# Generated by FakeRAM 2.0
VERSION 5.7 ;
BUSBITCHARS "[]" ;
PROPERTYDEFINITIONS
  MACRO width INTEGER ;
  MACRO depth INTEGER ;
  MACRO banks INTEGER ;
END PROPERTYDEFINITIONS
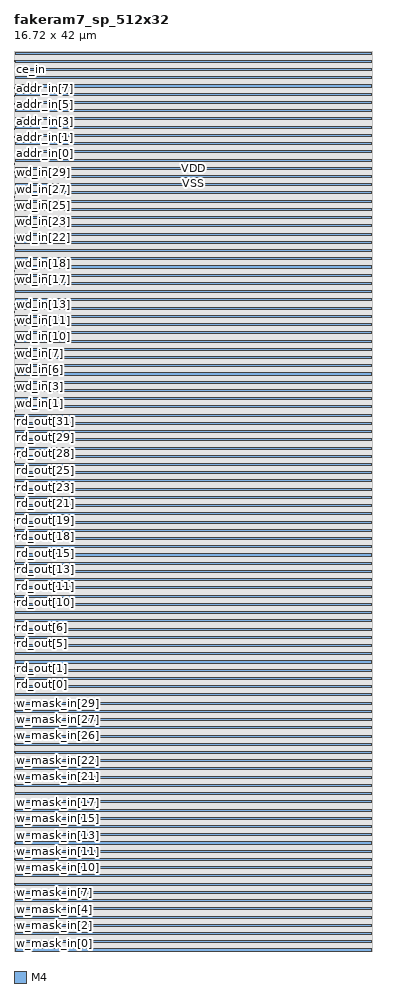
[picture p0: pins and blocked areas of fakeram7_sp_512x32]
MACRO fakeram7_sp_512x32
  PROPERTY width 32 ;
  PROPERTY depth 512 ;
  PROPERTY banks 4 ;
  FOREIGN fakeram7_sp_512x32 0 0 ;
  SYMMETRY X Y ;
  SIZE 16.720 BY 42.000 ;
  CLASS BLOCK ;
  PIN w_mask_in[0]
    DIRECTION INPUT ;
    USE SIGNAL ;
    SHAPE ABUTMENT ;
    PORT
      LAYER M4 ;
      RECT 0.000 0.048 0.024 0.072 ;
    END
  END w_mask_in[0]
  PIN w_mask_in[1]
    DIRECTION INPUT ;
    USE SIGNAL ;
    SHAPE ABUTMENT ;
    PORT
      LAYER M4 ;
      RECT 0.000 0.432 0.024 0.456 ;
    END
  END w_mask_in[1]
  PIN w_mask_in[2]
    DIRECTION INPUT ;
    USE SIGNAL ;
    SHAPE ABUTMENT ;
    PORT
      LAYER M4 ;
      RECT 0.000 0.816 0.024 0.840 ;
    END
  END w_mask_in[2]
  PIN w_mask_in[3]
    DIRECTION INPUT ;
    USE SIGNAL ;
    SHAPE ABUTMENT ;
    PORT
      LAYER M4 ;
      RECT 0.000 1.200 0.024 1.224 ;
    END
  END w_mask_in[3]
  PIN w_mask_in[4]
    DIRECTION INPUT ;
    USE SIGNAL ;
    SHAPE ABUTMENT ;
    PORT
      LAYER M4 ;
      RECT 0.000 1.584 0.024 1.608 ;
    END
  END w_mask_in[4]
  PIN w_mask_in[5]
    DIRECTION INPUT ;
    USE SIGNAL ;
    SHAPE ABUTMENT ;
    PORT
      LAYER M4 ;
      RECT 0.000 1.968 0.024 1.992 ;
    END
  END w_mask_in[5]
  PIN w_mask_in[6]
    DIRECTION INPUT ;
    USE SIGNAL ;
    SHAPE ABUTMENT ;
    PORT
      LAYER M4 ;
      RECT 0.000 2.352 0.024 2.376 ;
    END
  END w_mask_in[6]
  PIN w_mask_in[7]
    DIRECTION INPUT ;
    USE SIGNAL ;
    SHAPE ABUTMENT ;
    PORT
      LAYER M4 ;
      RECT 0.000 2.736 0.024 2.760 ;
    END
  END w_mask_in[7]
  PIN w_mask_in[8]
    DIRECTION INPUT ;
    USE SIGNAL ;
    SHAPE ABUTMENT ;
    PORT
      LAYER M4 ;
      RECT 0.000 3.120 0.024 3.144 ;
    END
  END w_mask_in[8]
  PIN w_mask_in[9]
    DIRECTION INPUT ;
    USE SIGNAL ;
    SHAPE ABUTMENT ;
    PORT
      LAYER M4 ;
      RECT 0.000 3.504 0.024 3.528 ;
    END
  END w_mask_in[9]
  PIN w_mask_in[10]
    DIRECTION INPUT ;
    USE SIGNAL ;
    SHAPE ABUTMENT ;
    PORT
      LAYER M4 ;
      RECT 0.000 3.888 0.024 3.912 ;
    END
  END w_mask_in[10]
  PIN w_mask_in[11]
    DIRECTION INPUT ;
    USE SIGNAL ;
    SHAPE ABUTMENT ;
    PORT
      LAYER M4 ;
      RECT 0.000 4.272 0.024 4.296 ;
    END
  END w_mask_in[11]
  PIN w_mask_in[12]
    DIRECTION INPUT ;
    USE SIGNAL ;
    SHAPE ABUTMENT ;
    PORT
      LAYER M4 ;
      RECT 0.000 4.656 0.024 4.680 ;
    END
  END w_mask_in[12]
  PIN w_mask_in[13]
    DIRECTION INPUT ;
    USE SIGNAL ;
    SHAPE ABUTMENT ;
    PORT
      LAYER M4 ;
      RECT 0.000 5.040 0.024 5.064 ;
    END
  END w_mask_in[13]
  PIN w_mask_in[14]
    DIRECTION INPUT ;
    USE SIGNAL ;
    SHAPE ABUTMENT ;
    PORT
      LAYER M4 ;
      RECT 0.000 5.424 0.024 5.448 ;
    END
  END w_mask_in[14]
  PIN w_mask_in[15]
    DIRECTION INPUT ;
    USE SIGNAL ;
    SHAPE ABUTMENT ;
    PORT
      LAYER M4 ;
      RECT 0.000 5.808 0.024 5.832 ;
    END
  END w_mask_in[15]
  PIN w_mask_in[16]
    DIRECTION INPUT ;
    USE SIGNAL ;
    SHAPE ABUTMENT ;
    PORT
      LAYER M4 ;
      RECT 0.000 6.192 0.024 6.216 ;
    END
  END w_mask_in[16]
  PIN w_mask_in[17]
    DIRECTION INPUT ;
    USE SIGNAL ;
    SHAPE ABUTMENT ;
    PORT
      LAYER M4 ;
      RECT 0.000 6.576 0.024 6.600 ;
    END
  END w_mask_in[17]
  PIN w_mask_in[18]
    DIRECTION INPUT ;
    USE SIGNAL ;
    SHAPE ABUTMENT ;
    PORT
      LAYER M4 ;
      RECT 0.000 6.960 0.024 6.984 ;
    END
  END w_mask_in[18]
  PIN w_mask_in[19]
    DIRECTION INPUT ;
    USE SIGNAL ;
    SHAPE ABUTMENT ;
    PORT
      LAYER M4 ;
      RECT 0.000 7.344 0.024 7.368 ;
    END
  END w_mask_in[19]
  PIN w_mask_in[20]
    DIRECTION INPUT ;
    USE SIGNAL ;
    SHAPE ABUTMENT ;
    PORT
      LAYER M4 ;
      RECT 0.000 7.728 0.024 7.752 ;
    END
  END w_mask_in[20]
  PIN w_mask_in[21]
    DIRECTION INPUT ;
    USE SIGNAL ;
    SHAPE ABUTMENT ;
    PORT
      LAYER M4 ;
      RECT 0.000 8.112 0.024 8.136 ;
    END
  END w_mask_in[21]
  PIN w_mask_in[22]
    DIRECTION INPUT ;
    USE SIGNAL ;
    SHAPE ABUTMENT ;
    PORT
      LAYER M4 ;
      RECT 0.000 8.496 0.024 8.520 ;
    END
  END w_mask_in[22]
  PIN w_mask_in[23]
    DIRECTION INPUT ;
    USE SIGNAL ;
    SHAPE ABUTMENT ;
    PORT
      LAYER M4 ;
      RECT 0.000 8.880 0.024 8.904 ;
    END
  END w_mask_in[23]
  PIN w_mask_in[24]
    DIRECTION INPUT ;
    USE SIGNAL ;
    SHAPE ABUTMENT ;
    PORT
      LAYER M4 ;
      RECT 0.000 9.264 0.024 9.288 ;
    END
  END w_mask_in[24]
  PIN w_mask_in[25]
    DIRECTION INPUT ;
    USE SIGNAL ;
    SHAPE ABUTMENT ;
    PORT
      LAYER M4 ;
      RECT 0.000 9.648 0.024 9.672 ;
    END
  END w_mask_in[25]
  PIN w_mask_in[26]
    DIRECTION INPUT ;
    USE SIGNAL ;
    SHAPE ABUTMENT ;
    PORT
      LAYER M4 ;
      RECT 0.000 10.032 0.024 10.056 ;
    END
  END w_mask_in[26]
  PIN w_mask_in[27]
    DIRECTION INPUT ;
    USE SIGNAL ;
    SHAPE ABUTMENT ;
    PORT
      LAYER M4 ;
      RECT 0.000 10.416 0.024 10.440 ;
    END
  END w_mask_in[27]
  PIN w_mask_in[28]
    DIRECTION INPUT ;
    USE SIGNAL ;
    SHAPE ABUTMENT ;
    PORT
      LAYER M4 ;
      RECT 0.000 10.800 0.024 10.824 ;
    END
  END w_mask_in[28]
  PIN w_mask_in[29]
    DIRECTION INPUT ;
    USE SIGNAL ;
    SHAPE ABUTMENT ;
    PORT
      LAYER M4 ;
      RECT 0.000 11.184 0.024 11.208 ;
    END
  END w_mask_in[29]
  PIN w_mask_in[30]
    DIRECTION INPUT ;
    USE SIGNAL ;
    SHAPE ABUTMENT ;
    PORT
      LAYER M4 ;
      RECT 0.000 11.568 0.024 11.592 ;
    END
  END w_mask_in[30]
  PIN w_mask_in[31]
    DIRECTION INPUT ;
    USE SIGNAL ;
    SHAPE ABUTMENT ;
    PORT
      LAYER M4 ;
      RECT 0.000 11.952 0.024 11.976 ;
    END
  END w_mask_in[31]
  PIN rd_out[0]
    DIRECTION OUTPUT ;
    USE SIGNAL ;
    SHAPE ABUTMENT ;
    PORT
      LAYER M4 ;
      RECT 0.000 12.432 0.024 12.456 ;
    END
  END rd_out[0]
  PIN rd_out[1]
    DIRECTION OUTPUT ;
    USE SIGNAL ;
    SHAPE ABUTMENT ;
    PORT
      LAYER M4 ;
      RECT 0.000 12.816 0.024 12.840 ;
    END
  END rd_out[1]
  PIN rd_out[2]
    DIRECTION OUTPUT ;
    USE SIGNAL ;
    SHAPE ABUTMENT ;
    PORT
      LAYER M4 ;
      RECT 0.000 13.200 0.024 13.224 ;
    END
  END rd_out[2]
  PIN rd_out[3]
    DIRECTION OUTPUT ;
    USE SIGNAL ;
    SHAPE ABUTMENT ;
    PORT
      LAYER M4 ;
      RECT 0.000 13.584 0.024 13.608 ;
    END
  END rd_out[3]
  PIN rd_out[4]
    DIRECTION OUTPUT ;
    USE SIGNAL ;
    SHAPE ABUTMENT ;
    PORT
      LAYER M4 ;
      RECT 0.000 13.968 0.024 13.992 ;
    END
  END rd_out[4]
  PIN rd_out[5]
    DIRECTION OUTPUT ;
    USE SIGNAL ;
    SHAPE ABUTMENT ;
    PORT
      LAYER M4 ;
      RECT 0.000 14.352 0.024 14.376 ;
    END
  END rd_out[5]
  PIN rd_out[6]
    DIRECTION OUTPUT ;
    USE SIGNAL ;
    SHAPE ABUTMENT ;
    PORT
      LAYER M4 ;
      RECT 0.000 14.736 0.024 14.760 ;
    END
  END rd_out[6]
  PIN rd_out[7]
    DIRECTION OUTPUT ;
    USE SIGNAL ;
    SHAPE ABUTMENT ;
    PORT
      LAYER M4 ;
      RECT 0.000 15.120 0.024 15.144 ;
    END
  END rd_out[7]
  PIN rd_out[8]
    DIRECTION OUTPUT ;
    USE SIGNAL ;
    SHAPE ABUTMENT ;
    PORT
      LAYER M4 ;
      RECT 0.000 15.504 0.024 15.528 ;
    END
  END rd_out[8]
  PIN rd_out[9]
    DIRECTION OUTPUT ;
    USE SIGNAL ;
    SHAPE ABUTMENT ;
    PORT
      LAYER M4 ;
      RECT 0.000 15.888 0.024 15.912 ;
    END
  END rd_out[9]
  PIN rd_out[10]
    DIRECTION OUTPUT ;
    USE SIGNAL ;
    SHAPE ABUTMENT ;
    PORT
      LAYER M4 ;
      RECT 0.000 16.272 0.024 16.296 ;
    END
  END rd_out[10]
  PIN rd_out[11]
    DIRECTION OUTPUT ;
    USE SIGNAL ;
    SHAPE ABUTMENT ;
    PORT
      LAYER M4 ;
      RECT 0.000 16.656 0.024 16.680 ;
    END
  END rd_out[11]
  PIN rd_out[12]
    DIRECTION OUTPUT ;
    USE SIGNAL ;
    SHAPE ABUTMENT ;
    PORT
      LAYER M4 ;
      RECT 0.000 17.040 0.024 17.064 ;
    END
  END rd_out[12]
  PIN rd_out[13]
    DIRECTION OUTPUT ;
    USE SIGNAL ;
    SHAPE ABUTMENT ;
    PORT
      LAYER M4 ;
      RECT 0.000 17.424 0.024 17.448 ;
    END
  END rd_out[13]
  PIN rd_out[14]
    DIRECTION OUTPUT ;
    USE SIGNAL ;
    SHAPE ABUTMENT ;
    PORT
      LAYER M4 ;
      RECT 0.000 17.808 0.024 17.832 ;
    END
  END rd_out[14]
  PIN rd_out[15]
    DIRECTION OUTPUT ;
    USE SIGNAL ;
    SHAPE ABUTMENT ;
    PORT
      LAYER M4 ;
      RECT 0.000 18.192 0.024 18.216 ;
    END
  END rd_out[15]
  PIN rd_out[16]
    DIRECTION OUTPUT ;
    USE SIGNAL ;
    SHAPE ABUTMENT ;
    PORT
      LAYER M4 ;
      RECT 0.000 18.576 0.024 18.600 ;
    END
  END rd_out[16]
  PIN rd_out[17]
    DIRECTION OUTPUT ;
    USE SIGNAL ;
    SHAPE ABUTMENT ;
    PORT
      LAYER M4 ;
      RECT 0.000 18.960 0.024 18.984 ;
    END
  END rd_out[17]
  PIN rd_out[18]
    DIRECTION OUTPUT ;
    USE SIGNAL ;
    SHAPE ABUTMENT ;
    PORT
      LAYER M4 ;
      RECT 0.000 19.344 0.024 19.368 ;
    END
  END rd_out[18]
  PIN rd_out[19]
    DIRECTION OUTPUT ;
    USE SIGNAL ;
    SHAPE ABUTMENT ;
    PORT
      LAYER M4 ;
      RECT 0.000 19.728 0.024 19.752 ;
    END
  END rd_out[19]
  PIN rd_out[20]
    DIRECTION OUTPUT ;
    USE SIGNAL ;
    SHAPE ABUTMENT ;
    PORT
      LAYER M4 ;
      RECT 0.000 20.112 0.024 20.136 ;
    END
  END rd_out[20]
  PIN rd_out[21]
    DIRECTION OUTPUT ;
    USE SIGNAL ;
    SHAPE ABUTMENT ;
    PORT
      LAYER M4 ;
      RECT 0.000 20.496 0.024 20.520 ;
    END
  END rd_out[21]
  PIN rd_out[22]
    DIRECTION OUTPUT ;
    USE SIGNAL ;
    SHAPE ABUTMENT ;
    PORT
      LAYER M4 ;
      RECT 0.000 20.880 0.024 20.904 ;
    END
  END rd_out[22]
  PIN rd_out[23]
    DIRECTION OUTPUT ;
    USE SIGNAL ;
    SHAPE ABUTMENT ;
    PORT
      LAYER M4 ;
      RECT 0.000 21.264 0.024 21.288 ;
    END
  END rd_out[23]
  PIN rd_out[24]
    DIRECTION OUTPUT ;
    USE SIGNAL ;
    SHAPE ABUTMENT ;
    PORT
      LAYER M4 ;
      RECT 0.000 21.648 0.024 21.672 ;
    END
  END rd_out[24]
  PIN rd_out[25]
    DIRECTION OUTPUT ;
    USE SIGNAL ;
    SHAPE ABUTMENT ;
    PORT
      LAYER M4 ;
      RECT 0.000 22.032 0.024 22.056 ;
    END
  END rd_out[25]
  PIN rd_out[26]
    DIRECTION OUTPUT ;
    USE SIGNAL ;
    SHAPE ABUTMENT ;
    PORT
      LAYER M4 ;
      RECT 0.000 22.416 0.024 22.440 ;
    END
  END rd_out[26]
  PIN rd_out[27]
    DIRECTION OUTPUT ;
    USE SIGNAL ;
    SHAPE ABUTMENT ;
    PORT
      LAYER M4 ;
      RECT 0.000 22.800 0.024 22.824 ;
    END
  END rd_out[27]
  PIN rd_out[28]
    DIRECTION OUTPUT ;
    USE SIGNAL ;
    SHAPE ABUTMENT ;
    PORT
      LAYER M4 ;
      RECT 0.000 23.184 0.024 23.208 ;
    END
  END rd_out[28]
  PIN rd_out[29]
    DIRECTION OUTPUT ;
    USE SIGNAL ;
    SHAPE ABUTMENT ;
    PORT
      LAYER M4 ;
      RECT 0.000 23.568 0.024 23.592 ;
    END
  END rd_out[29]
  PIN rd_out[30]
    DIRECTION OUTPUT ;
    USE SIGNAL ;
    SHAPE ABUTMENT ;
    PORT
      LAYER M4 ;
      RECT 0.000 23.952 0.024 23.976 ;
    END
  END rd_out[30]
  PIN rd_out[31]
    DIRECTION OUTPUT ;
    USE SIGNAL ;
    SHAPE ABUTMENT ;
    PORT
      LAYER M4 ;
      RECT 0.000 24.336 0.024 24.360 ;
    END
  END rd_out[31]
  PIN wd_in[0]
    DIRECTION INPUT ;
    USE SIGNAL ;
    SHAPE ABUTMENT ;
    PORT
      LAYER M4 ;
      RECT 0.000 24.816 0.024 24.840 ;
    END
  END wd_in[0]
  PIN wd_in[1]
    DIRECTION INPUT ;
    USE SIGNAL ;
    SHAPE ABUTMENT ;
    PORT
      LAYER M4 ;
      RECT 0.000 25.200 0.024 25.224 ;
    END
  END wd_in[1]
  PIN wd_in[2]
    DIRECTION INPUT ;
    USE SIGNAL ;
    SHAPE ABUTMENT ;
    PORT
      LAYER M4 ;
      RECT 0.000 25.584 0.024 25.608 ;
    END
  END wd_in[2]
  PIN wd_in[3]
    DIRECTION INPUT ;
    USE SIGNAL ;
    SHAPE ABUTMENT ;
    PORT
      LAYER M4 ;
      RECT 0.000 25.968 0.024 25.992 ;
    END
  END wd_in[3]
  PIN wd_in[4]
    DIRECTION INPUT ;
    USE SIGNAL ;
    SHAPE ABUTMENT ;
    PORT
      LAYER M4 ;
      RECT 0.000 26.352 0.024 26.376 ;
    END
  END wd_in[4]
  PIN wd_in[5]
    DIRECTION INPUT ;
    USE SIGNAL ;
    SHAPE ABUTMENT ;
    PORT
      LAYER M4 ;
      RECT 0.000 26.736 0.024 26.760 ;
    END
  END wd_in[5]
  PIN wd_in[6]
    DIRECTION INPUT ;
    USE SIGNAL ;
    SHAPE ABUTMENT ;
    PORT
      LAYER M4 ;
      RECT 0.000 27.120 0.024 27.144 ;
    END
  END wd_in[6]
  PIN wd_in[7]
    DIRECTION INPUT ;
    USE SIGNAL ;
    SHAPE ABUTMENT ;
    PORT
      LAYER M4 ;
      RECT 0.000 27.504 0.024 27.528 ;
    END
  END wd_in[7]
  PIN wd_in[8]
    DIRECTION INPUT ;
    USE SIGNAL ;
    SHAPE ABUTMENT ;
    PORT
      LAYER M4 ;
      RECT 0.000 27.888 0.024 27.912 ;
    END
  END wd_in[8]
  PIN wd_in[9]
    DIRECTION INPUT ;
    USE SIGNAL ;
    SHAPE ABUTMENT ;
    PORT
      LAYER M4 ;
      RECT 0.000 28.272 0.024 28.296 ;
    END
  END wd_in[9]
  PIN wd_in[10]
    DIRECTION INPUT ;
    USE SIGNAL ;
    SHAPE ABUTMENT ;
    PORT
      LAYER M4 ;
      RECT 0.000 28.656 0.024 28.680 ;
    END
  END wd_in[10]
  PIN wd_in[11]
    DIRECTION INPUT ;
    USE SIGNAL ;
    SHAPE ABUTMENT ;
    PORT
      LAYER M4 ;
      RECT 0.000 29.040 0.024 29.064 ;
    END
  END wd_in[11]
  PIN wd_in[12]
    DIRECTION INPUT ;
    USE SIGNAL ;
    SHAPE ABUTMENT ;
    PORT
      LAYER M4 ;
      RECT 0.000 29.424 0.024 29.448 ;
    END
  END wd_in[12]
  PIN wd_in[13]
    DIRECTION INPUT ;
    USE SIGNAL ;
    SHAPE ABUTMENT ;
    PORT
      LAYER M4 ;
      RECT 0.000 29.808 0.024 29.832 ;
    END
  END wd_in[13]
  PIN wd_in[14]
    DIRECTION INPUT ;
    USE SIGNAL ;
    SHAPE ABUTMENT ;
    PORT
      LAYER M4 ;
      RECT 0.000 30.192 0.024 30.216 ;
    END
  END wd_in[14]
  PIN wd_in[15]
    DIRECTION INPUT ;
    USE SIGNAL ;
    SHAPE ABUTMENT ;
    PORT
      LAYER M4 ;
      RECT 0.000 30.576 0.024 30.600 ;
    END
  END wd_in[15]
  PIN wd_in[16]
    DIRECTION INPUT ;
    USE SIGNAL ;
    SHAPE ABUTMENT ;
    PORT
      LAYER M4 ;
      RECT 0.000 30.960 0.024 30.984 ;
    END
  END wd_in[16]
  PIN wd_in[17]
    DIRECTION INPUT ;
    USE SIGNAL ;
    SHAPE ABUTMENT ;
    PORT
      LAYER M4 ;
      RECT 0.000 31.344 0.024 31.368 ;
    END
  END wd_in[17]
  PIN wd_in[18]
    DIRECTION INPUT ;
    USE SIGNAL ;
    SHAPE ABUTMENT ;
    PORT
      LAYER M4 ;
      RECT 0.000 31.728 0.024 31.752 ;
    END
  END wd_in[18]
  PIN wd_in[19]
    DIRECTION INPUT ;
    USE SIGNAL ;
    SHAPE ABUTMENT ;
    PORT
      LAYER M4 ;
      RECT 0.000 32.112 0.024 32.136 ;
    END
  END wd_in[19]
  PIN wd_in[20]
    DIRECTION INPUT ;
    USE SIGNAL ;
    SHAPE ABUTMENT ;
    PORT
      LAYER M4 ;
      RECT 0.000 32.496 0.024 32.520 ;
    END
  END wd_in[20]
  PIN wd_in[21]
    DIRECTION INPUT ;
    USE SIGNAL ;
    SHAPE ABUTMENT ;
    PORT
      LAYER M4 ;
      RECT 0.000 32.880 0.024 32.904 ;
    END
  END wd_in[21]
  PIN wd_in[22]
    DIRECTION INPUT ;
    USE SIGNAL ;
    SHAPE ABUTMENT ;
    PORT
      LAYER M4 ;
      RECT 0.000 33.264 0.024 33.288 ;
    END
  END wd_in[22]
  PIN wd_in[23]
    DIRECTION INPUT ;
    USE SIGNAL ;
    SHAPE ABUTMENT ;
    PORT
      LAYER M4 ;
      RECT 0.000 33.648 0.024 33.672 ;
    END
  END wd_in[23]
  PIN wd_in[24]
    DIRECTION INPUT ;
    USE SIGNAL ;
    SHAPE ABUTMENT ;
    PORT
      LAYER M4 ;
      RECT 0.000 34.032 0.024 34.056 ;
    END
  END wd_in[24]
  PIN wd_in[25]
    DIRECTION INPUT ;
    USE SIGNAL ;
    SHAPE ABUTMENT ;
    PORT
      LAYER M4 ;
      RECT 0.000 34.416 0.024 34.440 ;
    END
  END wd_in[25]
  PIN wd_in[26]
    DIRECTION INPUT ;
    USE SIGNAL ;
    SHAPE ABUTMENT ;
    PORT
      LAYER M4 ;
      RECT 0.000 34.800 0.024 34.824 ;
    END
  END wd_in[26]
  PIN wd_in[27]
    DIRECTION INPUT ;
    USE SIGNAL ;
    SHAPE ABUTMENT ;
    PORT
      LAYER M4 ;
      RECT 0.000 35.184 0.024 35.208 ;
    END
  END wd_in[27]
  PIN wd_in[28]
    DIRECTION INPUT ;
    USE SIGNAL ;
    SHAPE ABUTMENT ;
    PORT
      LAYER M4 ;
      RECT 0.000 35.568 0.024 35.592 ;
    END
  END wd_in[28]
  PIN wd_in[29]
    DIRECTION INPUT ;
    USE SIGNAL ;
    SHAPE ABUTMENT ;
    PORT
      LAYER M4 ;
      RECT 0.000 35.952 0.024 35.976 ;
    END
  END wd_in[29]
  PIN wd_in[30]
    DIRECTION INPUT ;
    USE SIGNAL ;
    SHAPE ABUTMENT ;
    PORT
      LAYER M4 ;
      RECT 0.000 36.336 0.024 36.360 ;
    END
  END wd_in[30]
  PIN wd_in[31]
    DIRECTION INPUT ;
    USE SIGNAL ;
    SHAPE ABUTMENT ;
    PORT
      LAYER M4 ;
      RECT 0.000 36.720 0.024 36.744 ;
    END
  END wd_in[31]
  PIN addr_in[0]
    DIRECTION INPUT ;
    USE SIGNAL ;
    SHAPE ABUTMENT ;
    PORT
      LAYER M4 ;
      RECT 0.000 37.200 0.024 37.224 ;
    END
  END addr_in[0]
  PIN addr_in[1]
    DIRECTION INPUT ;
    USE SIGNAL ;
    SHAPE ABUTMENT ;
    PORT
      LAYER M4 ;
      RECT 0.000 37.584 0.024 37.608 ;
    END
  END addr_in[1]
  PIN addr_in[2]
    DIRECTION INPUT ;
    USE SIGNAL ;
    SHAPE ABUTMENT ;
    PORT
      LAYER M4 ;
      RECT 0.000 37.968 0.024 37.992 ;
    END
  END addr_in[2]
  PIN addr_in[3]
    DIRECTION INPUT ;
    USE SIGNAL ;
    SHAPE ABUTMENT ;
    PORT
      LAYER M4 ;
      RECT 0.000 38.352 0.024 38.376 ;
    END
  END addr_in[3]
  PIN addr_in[4]
    DIRECTION INPUT ;
    USE SIGNAL ;
    SHAPE ABUTMENT ;
    PORT
      LAYER M4 ;
      RECT 0.000 38.736 0.024 38.760 ;
    END
  END addr_in[4]
  PIN addr_in[5]
    DIRECTION INPUT ;
    USE SIGNAL ;
    SHAPE ABUTMENT ;
    PORT
      LAYER M4 ;
      RECT 0.000 39.120 0.024 39.144 ;
    END
  END addr_in[5]
  PIN addr_in[6]
    DIRECTION INPUT ;
    USE SIGNAL ;
    SHAPE ABUTMENT ;
    PORT
      LAYER M4 ;
      RECT 0.000 39.504 0.024 39.528 ;
    END
  END addr_in[6]
  PIN addr_in[7]
    DIRECTION INPUT ;
    USE SIGNAL ;
    SHAPE ABUTMENT ;
    PORT
      LAYER M4 ;
      RECT 0.000 39.888 0.024 39.912 ;
    END
  END addr_in[7]
  PIN addr_in[8]
    DIRECTION INPUT ;
    USE SIGNAL ;
    SHAPE ABUTMENT ;
    PORT
      LAYER M4 ;
      RECT 0.000 40.272 0.024 40.296 ;
    END
  END addr_in[8]
  PIN we_in
    DIRECTION INPUT ;
    USE SIGNAL ;
    SHAPE ABUTMENT ;
    PORT
      LAYER M4 ;
      RECT 0.000 40.752 0.024 40.776 ;
    END
  END we_in
  PIN ce_in
    DIRECTION INPUT ;
    USE SIGNAL ;
    SHAPE ABUTMENT ;
    PORT
      LAYER M4 ;
      RECT 0.000 41.136 0.024 41.160 ;
    END
  END ce_in
  PIN clk
    DIRECTION INPUT ;
    USE SIGNAL ;
    SHAPE ABUTMENT ;
    PORT
      LAYER M4 ;
      RECT 0.000 41.520 0.024 41.544 ;
    END
  END clk
  PIN VSS
    DIRECTION INOUT ;
    USE GROUND ;
    PORT
      LAYER M4 ;
      RECT 0.048 0.000 16.672 0.096 ;
      RECT 0.048 0.768 16.672 0.864 ;
      RECT 0.048 1.536 16.672 1.632 ;
      RECT 0.048 2.304 16.672 2.400 ;
      RECT 0.048 3.072 16.672 3.168 ;
      RECT 0.048 3.840 16.672 3.936 ;
      RECT 0.048 4.608 16.672 4.704 ;
      RECT 0.048 5.376 16.672 5.472 ;
      RECT 0.048 6.144 16.672 6.240 ;
      RECT 0.048 6.912 16.672 7.008 ;
      RECT 0.048 7.680 16.672 7.776 ;
      RECT 0.048 8.448 16.672 8.544 ;
      RECT 0.048 9.216 16.672 9.312 ;
      RECT 0.048 9.984 16.672 10.080 ;
      RECT 0.048 10.752 16.672 10.848 ;
      RECT 0.048 11.520 16.672 11.616 ;
      RECT 0.048 12.288 16.672 12.384 ;
      RECT 0.048 13.056 16.672 13.152 ;
      RECT 0.048 13.824 16.672 13.920 ;
      RECT 0.048 14.592 16.672 14.688 ;
      RECT 0.048 15.360 16.672 15.456 ;
      RECT 0.048 16.128 16.672 16.224 ;
      RECT 0.048 16.896 16.672 16.992 ;
      RECT 0.048 17.664 16.672 17.760 ;
      RECT 0.048 18.432 16.672 18.528 ;
      RECT 0.048 19.200 16.672 19.296 ;
      RECT 0.048 19.968 16.672 20.064 ;
      RECT 0.048 20.736 16.672 20.832 ;
      RECT 0.048 21.504 16.672 21.600 ;
      RECT 0.048 22.272 16.672 22.368 ;
      RECT 0.048 23.040 16.672 23.136 ;
      RECT 0.048 23.808 16.672 23.904 ;
      RECT 0.048 24.576 16.672 24.672 ;
      RECT 0.048 25.344 16.672 25.440 ;
      RECT 0.048 26.112 16.672 26.208 ;
      RECT 0.048 26.880 16.672 26.976 ;
      RECT 0.048 27.648 16.672 27.744 ;
      RECT 0.048 28.416 16.672 28.512 ;
      RECT 0.048 29.184 16.672 29.280 ;
      RECT 0.048 29.952 16.672 30.048 ;
      RECT 0.048 30.720 16.672 30.816 ;
      RECT 0.048 31.488 16.672 31.584 ;
      RECT 0.048 32.256 16.672 32.352 ;
      RECT 0.048 33.024 16.672 33.120 ;
      RECT 0.048 33.792 16.672 33.888 ;
      RECT 0.048 34.560 16.672 34.656 ;
      RECT 0.048 35.328 16.672 35.424 ;
      RECT 0.048 36.096 16.672 36.192 ;
      RECT 0.048 36.864 16.672 36.960 ;
      RECT 0.048 37.632 16.672 37.728 ;
      RECT 0.048 38.400 16.672 38.496 ;
      RECT 0.048 39.168 16.672 39.264 ;
      RECT 0.048 39.936 16.672 40.032 ;
      RECT 0.048 40.704 16.672 40.800 ;
      RECT 0.048 41.472 16.672 41.568 ;
    END
  END VSS
  PIN VDD
    DIRECTION INOUT ;
    USE POWER ;
    PORT
      LAYER M4 ;
      RECT 0.048 0.384 16.672 0.480 ;
      RECT 0.048 1.152 16.672 1.248 ;
      RECT 0.048 1.920 16.672 2.016 ;
      RECT 0.048 2.688 16.672 2.784 ;
      RECT 0.048 3.456 16.672 3.552 ;
      RECT 0.048 4.224 16.672 4.320 ;
      RECT 0.048 4.992 16.672 5.088 ;
      RECT 0.048 5.760 16.672 5.856 ;
      RECT 0.048 6.528 16.672 6.624 ;
      RECT 0.048 7.296 16.672 7.392 ;
      RECT 0.048 8.064 16.672 8.160 ;
      RECT 0.048 8.832 16.672 8.928 ;
      RECT 0.048 9.600 16.672 9.696 ;
      RECT 0.048 10.368 16.672 10.464 ;
      RECT 0.048 11.136 16.672 11.232 ;
      RECT 0.048 11.904 16.672 12.000 ;
      RECT 0.048 12.672 16.672 12.768 ;
      RECT 0.048 13.440 16.672 13.536 ;
      RECT 0.048 14.208 16.672 14.304 ;
      RECT 0.048 14.976 16.672 15.072 ;
      RECT 0.048 15.744 16.672 15.840 ;
      RECT 0.048 16.512 16.672 16.608 ;
      RECT 0.048 17.280 16.672 17.376 ;
      RECT 0.048 18.048 16.672 18.144 ;
      RECT 0.048 18.816 16.672 18.912 ;
      RECT 0.048 19.584 16.672 19.680 ;
      RECT 0.048 20.352 16.672 20.448 ;
      RECT 0.048 21.120 16.672 21.216 ;
      RECT 0.048 21.888 16.672 21.984 ;
      RECT 0.048 22.656 16.672 22.752 ;
      RECT 0.048 23.424 16.672 23.520 ;
      RECT 0.048 24.192 16.672 24.288 ;
      RECT 0.048 24.960 16.672 25.056 ;
      RECT 0.048 25.728 16.672 25.824 ;
      RECT 0.048 26.496 16.672 26.592 ;
      RECT 0.048 27.264 16.672 27.360 ;
      RECT 0.048 28.032 16.672 28.128 ;
      RECT 0.048 28.800 16.672 28.896 ;
      RECT 0.048 29.568 16.672 29.664 ;
      RECT 0.048 30.336 16.672 30.432 ;
      RECT 0.048 31.104 16.672 31.200 ;
      RECT 0.048 31.872 16.672 31.968 ;
      RECT 0.048 32.640 16.672 32.736 ;
      RECT 0.048 33.408 16.672 33.504 ;
      RECT 0.048 34.176 16.672 34.272 ;
      RECT 0.048 34.944 16.672 35.040 ;
      RECT 0.048 35.712 16.672 35.808 ;
      RECT 0.048 36.480 16.672 36.576 ;
      RECT 0.048 37.248 16.672 37.344 ;
      RECT 0.048 38.016 16.672 38.112 ;
      RECT 0.048 38.784 16.672 38.880 ;
      RECT 0.048 39.552 16.672 39.648 ;
      RECT 0.048 40.320 16.672 40.416 ;
      RECT 0.048 41.088 16.672 41.184 ;
      RECT 0.048 41.856 16.672 41.952 ;
    END
  END VDD
  OBS
    LAYER M1 ;
    RECT 0 0 16.720 42.000 ;
    LAYER M2 ;
    RECT 0 0 16.720 42.000 ;
    LAYER M3 ;
    RECT 0 0 16.720 42.000 ;
    LAYER M4 ;
    RECT 0 0 16.720 42.000 ;
  END
END fakeram7_sp_512x32

END LIBRARY
